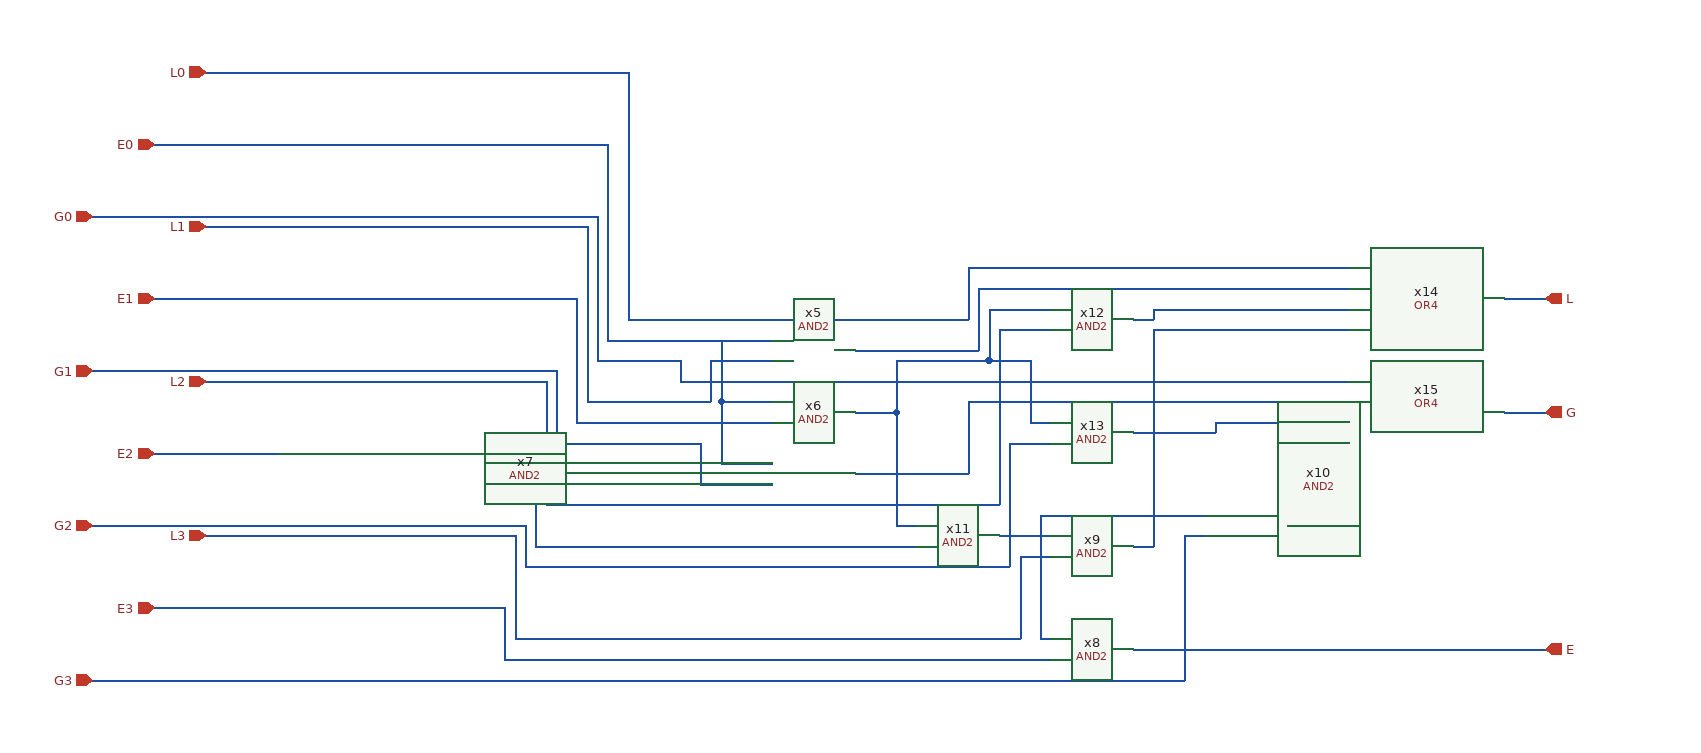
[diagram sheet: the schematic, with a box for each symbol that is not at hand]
v {xschem version=3.4.5 file_version=1.2
}
G {}
K {}
V {}
S {}
E {}
N 1430 -2420 1760 -2420 {
lab=L0}
N 1760 -2470 1760 -2420 {
lab=L0}
N 1760 -2470 1870 -2470 {
lab=L0}
N 1430 -2400 1570 -2400 {
lab=E0}
N 1650 -2390 1770 -2390 {
lab=#net1}
N 1770 -2450 1770 -2390 {
lab=#net1}
N 1770 -2450 1870 -2450 {
lab=#net1}
N 1430 -2340 1510 -2340 {
lab=L1}
N 1510 -2380 1510 -2340 {
lab=L1}
N 1510 -2380 1570 -2380 {
lab=L1}
N 1430 -2320 1570 -2320 {
lab=E1}
N 1520 -2340 1570 -2340 {
lab=E0}
N 1520 -2400 1520 -2340 {
lab=E0}
N 1430 -2380 1480 -2380 {
lab=G0}
N 1480 -2380 1480 -2360 {
lab=G0}
N 1480 -2360 1870 -2360 {
lab=G0}
N 1520 -2340 1520 -2280 {
lab=E0}
N 1520 -2280 1570 -2280 {
lab=E0}
N 1500 -2260 1570 -2260 {
lab=G1}
N 1500 -2300 1500 -2260 {
lab=G1}
N 1430 -2300 1500 -2300 {
lab=G1}
N 1650 -2270 1760 -2270 {
lab=#net2}
N 1760 -2340 1760 -2270 {
lab=#net2}
N 1760 -2340 1870 -2340 {
lab=#net2}
N 1650 -2330 1690 -2330 {
lab=#net3}
N 1690 -2330 1690 -2220 {
lab=#net3}
N 1690 -2220 1710 -2220 {
lab=#net3}
N 1430 -2200 1710 -2200 {
lab=E2}
N 1690 -2380 1690 -2330 {
lab=#net3}
N 1780 -2430 1810 -2430 {
lab=#net3}
N 1780 -2430 1780 -2380 {
lab=#net3}
N 1690 -2380 1780 -2380 {
lab=#net3}
N 1500 -2240 1780 -2240 {
lab=L2}
N 1780 -2240 1790 -2240 {
lab=L2}
N 1790 -2410 1790 -2240 {
lab=L2}
N 1790 -2410 1810 -2410 {
lab=L2}
N 1810 -2430 1840 -2430 {
lab=#net3}
N 1810 -2410 1840 -2410 {
lab=L2}
N 1780 -2380 1820 -2380 {
lab=#net3}
N 1820 -2380 1820 -2320 {
lab=#net3}
N 1820 -2320 1840 -2320 {
lab=#net3}
N 1820 -2300 1840 -2300 {
lab=G2}
N 1790 -2210 1840 -2210 {
lab=#net4}
N 1830 -2230 1830 -2210 {
lab=#net4}
N 1830 -2230 1990 -2230 {
lab=#net4}
N 1870 -2470 2130 -2470 {
lab=L0}
N 1870 -2450 2130 -2450 {
lab=#net1}
N 1870 -2360 2130 -2360 {
lab=G0}
N 1870 -2340 2130 -2340 {
lab=#net2}
N 1920 -2200 1940 -2200 {
lab=#net5}
N 1940 -2410 1940 -2200 {
lab=#net5}
N 1940 -2410 2130 -2410 {
lab=#net5}
N 2070 -2220 2090 -2220 {
lab=#net6}
N 2090 -2300 2090 -2220 {
lab=#net6}
N 2090 -2300 2130 -2300 {
lab=#net6}
N 1810 -2300 1820 -2300 {
lab=G2}
N 1800 -2300 1810 -2300 {
lab=G2}
N 1800 -2300 1800 -2180 {
lab=G2}
N 1430 -2180 1800 -2180 {
lab=G2}
N 1810 -2190 1840 -2190 {
lab=L3}
N 1810 -2190 1810 -2110 {
lab=L3}
N 1430 -2110 1810 -2110 {
lab=L3}
N 1830 -2210 1830 -2120 {
lab=#net4}
N 1430 -2090 1840 -2090 {
lab=E3}
N 1430 -2070 1970 -2070 {
lab=G3}
N 1970 -2210 1970 -2070 {
lab=G3}
N 1970 -2210 1990 -2210 {
lab=G3}
N 1920 -2100 2320 -2100 {
lab=E}
N 2280 -2330 2320 -2330 {
lab=G}
N 2280 -2440 2320 -2440 {
lab=L}
N 1920 -2420 1940 -2420 {
lab=#net7}
N 1940 -2430 1940 -2420 {
lab=#net7}
N 1940 -2430 2130 -2430 {
lab=#net7}
N 1920 -2310 2000 -2310 {
lab=#net8}
N 2000 -2320 2000 -2310 {
lab=#net8}
N 2000 -2320 2130 -2320 {
lab=#net8}
N 1830 -2120 1830 -2110 {
lab=#net4}
N 1830 -2110 1840 -2110 {
lab=#net4}
N 1430 -2660 1430 -2420 {
lab=L0}
N 1090 -2660 1430 -2660 {
lab=L0}
N 1090 -2590 1410 -2590 {
lab=E0}
N 1410 -2590 1410 -2400 {
lab=E0}
N 1410 -2400 1430 -2400 {
lab=E0}
N 1400 -2380 1430 -2380 {
lab=G0}
N 1400 -2520 1400 -2380 {
lab=G0}
N 1090 -2520 1400 -2520 {
lab=G0}
N 1390 -2340 1430 -2340 {
lab=L1}
N 1390 -2510 1390 -2340 {
lab=L1}
N 1090 -2510 1390 -2510 {
lab=L1}
N 1090 -2440 1380 -2440 {
lab=E1}
N 1380 -2440 1380 -2320 {
lab=E1}
N 1380 -2320 1430 -2320 {
lab=E1}
N 1360 -2300 1430 -2300 {
lab=G1}
N 1360 -2370 1360 -2300 {
lab=G1}
N 1090 -2370 1360 -2370 {
lab=G1}
N 1350 -2240 1500 -2240 {
lab=L2}
N 1350 -2360 1350 -2240 {
lab=L2}
N 1090 -2360 1350 -2360 {
lab=L2}
N 1090 -2290 1340 -2290 {
lab=E2}
N 1340 -2290 1340 -2200 {
lab=E2}
N 1340 -2200 1430 -2200 {
lab=E2}
N 1090 -2220 1330 -2220 {
lab=G2}
N 1330 -2220 1330 -2180 {
lab=G2}
N 1330 -2180 1430 -2180 {
lab=G2}
N 1090 -2210 1320 -2210 {
lab=L3}
N 1320 -2210 1320 -2110 {
lab=L3}
N 1320 -2110 1430 -2110 {
lab=L3}
N 1310 -2090 1430 -2090 {
lab=E3}
N 1310 -2140 1310 -2090 {
lab=E3}
N 1090 -2140 1310 -2140 {
lab=E3}
N 1090 -2070 1430 -2070 {
lab=G3}
N 1020 -2660 1090 -2660 {
lab=L0}
N 970 -2590 1090 -2590 {
lab=E0}
N 910 -2520 1090 -2520 {
lab=G0}
N 1020 -2510 1090 -2510 {
lab=L1}
N 970 -2440 1090 -2440 {
lab=E1}
N 910 -2370 1090 -2370 {
lab=G1}
N 1020 -2360 1090 -2360 {
lab=L2}
N 970 -2290 1100 -2290 {
lab=E2}
N 910 -2220 1090 -2220 {
lab=G2}
N 1020 -2210 1090 -2210 {
lab=L3}
N 970 -2140 1090 -2140 {
lab=E3}
N 910 -2070 1090 -2070 {
lab=G3}
C {AND2.sym} 1610 -2390 0 0 {name=x5}
C {AND2.sym} 1610 -2330 0 0 {name=x6}
C {AND2.sym} 1610 -2270 0 0 {name=x7}
C {AND2.sym} 1880 -2100 0 0 {name=x8}
C {AND2.sym} 1880 -2200 0 0 {name=x9}
C {AND2.sym} 2030 -2220 0 0 {name=x10}
C {AND2.sym} 1750 -2210 0 0 {name=x11}
C {AND2.sym} 1880 -2420 0 0 {name=x12}
C {AND2.sym} 1880 -2310 0 0 {name=x13}
C {OR4.sym} 2280 -2440 0 0 {name=x14}
C {OR4.sym} 2280 -2330 0 0 {name=x15}
C {devices/opin.sym} 2320 -2440 0 0 {name=p1 sig_type=std_logic lab=L}
C {devices/opin.sym} 2320 -2330 0 0 {name=p2 sig_type=std_logic lab=G}
C {devices/opin.sym} 2320 -2100 0 0 {name=p3 sig_type=std_logic lab=E}
C {devices/ipin.sym} 1020 -2660 0 0 {name=p16 sig_type=std_logic lab=L0}
C {devices/ipin.sym} 970 -2590 0 0 {name=p17 sig_type=std_logic lab=E0}
C {devices/ipin.sym} 910 -2520 0 0 {name=p4 sig_type=std_logic lab=G0}
C {devices/ipin.sym} 910 -2370 0 0 {name=p5 sig_type=std_logic lab=G1}
C {devices/ipin.sym} 910 -2220 0 0 {name=p6 sig_type=std_logic lab=G2}
C {devices/ipin.sym} 910 -2070 0 0 {name=p7 sig_type=std_logic lab=G3}
C {devices/ipin.sym} 970 -2440 0 0 {name=p8 sig_type=std_logic lab=E1}
C {devices/ipin.sym} 970 -2290 0 0 {name=p9 sig_type=std_logic lab=E2}
C {devices/ipin.sym} 970 -2140 0 0 {name=p10 sig_type=std_logic lab=E3}
C {devices/ipin.sym} 1020 -2510 0 0 {name=p11 sig_type=std_logic lab=L1}
C {devices/ipin.sym} 1020 -2360 0 0 {name=p12 sig_type=std_logic lab=L2}
C {devices/ipin.sym} 1020 -2210 0 0 {name=p13 sig_type=std_logic lab=L3}
